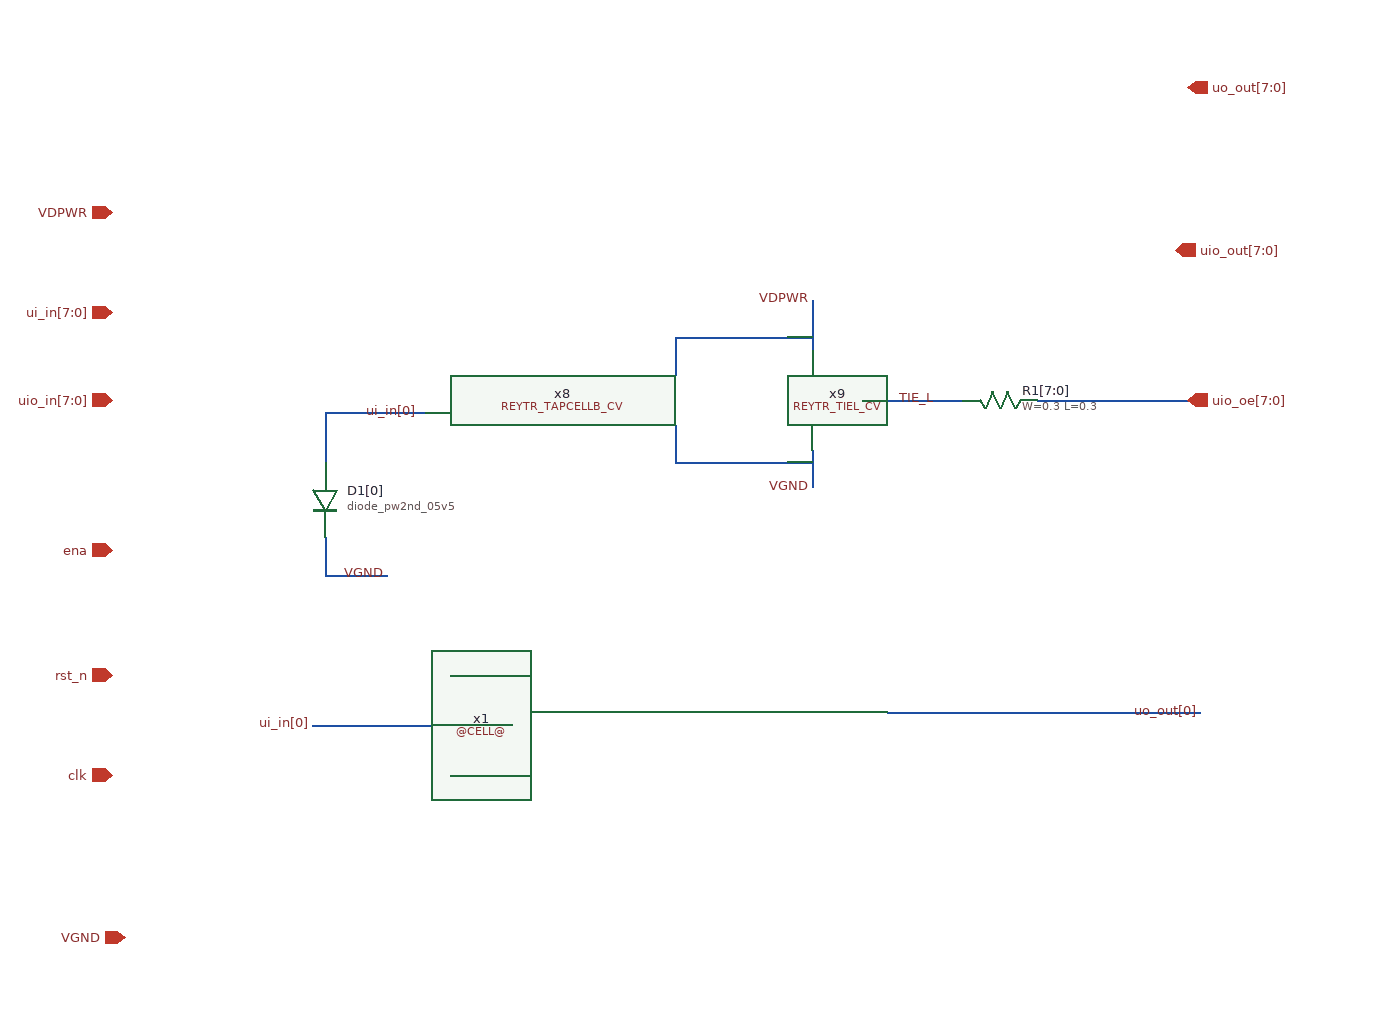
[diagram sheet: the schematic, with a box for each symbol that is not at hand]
v {xschem version=3.4.7 file_version=1.2}
G {}
K {}
V {}
S {}
E {}
N 70 -550 70 -510 {lab=VDPWR}
N 70 -430 70 -400 {lab=VGND}
N -40 -520 -40 -490 {lab=VDPWR}
N -40 -520 70 -520 {lab=VDPWR}
N -40 -450 -40 -420 {lab=VGND}
N -40 -420 70 -420 {lab=VGND}
N 110 -470 190 -470 {lab=TIE_L}
N 250 -470 300 -470 {lab=uio_oe[7:0]}
N 300 -470 370 -470 {lab=uio_oe[7:0]}
N 310 -220 380 -220 {lab=uo_out[0]}
N 130 -220 180 -220 {lab=uo_out[0]}
N -240 -210 -170 -210 {lab=ui_in[0]}
N -220 -250 -170 -250 {lab=VDPWR}
N -220 -170 -170 -170 {lab=VGND}
N 180 -220 190 -220 {lab=uo_out[0]}
N 250 -220 310 -220 {lab=uo_out[0]}
N -330 -210 -300 -210 {lab=ui_in[0]}
N 190 -220 250 -220 {lab=uo_out[0]}
N -300 -210 -240 -210 {lab=ui_in[0]}
N -320 -360 -320 -330 {lab=VGND}
N -320 -330 -270 -330 {lab=VGND}
N -320 -460 -320 -420 {lab=ui_in[0]}
N -320 -460 -240 -460 {lab=ui_in[0]}
C {devices/opin.sym} 370 -720 0 0 {name=p4 lab=uo_out[7:0]}
C {devices/opin.sym} 360 -590 0 0 {name=p6 lab=uio_out[7:0]}
C {REY_TR_SKY130A/REYTR_TAPCELLB_CV.sym} -40 -470 0 0 {name=x8 }
C {REY_TR_SKY130A/REYTR_TIEL_CV.sym} 70 -430 0 0 {name=x9 }
C {devices/lab_wire.sym} 70 -550 0 0 {name=p30 sig_type=std_logic lab=VDPWR}
C {devices/lab_wire.sym} 70 -400 0 0 {name=p31 sig_type=std_logic lab=VGND}
C {sky130_fd_pr/res_generic_m4.sym} 220 -470 1 0 {name=R1[7:0]
W=0.3
L=0.3
model=res_generic_m4
mult=1}
C {devices/opin.sym} 370 -470 0 0 {name=p32 lab=uio_oe[7:0]}
C {devices/lab_wire.sym} 170 -470 0 0 {name=p7 sig_type=std_logic lab=TIE_L}
C {devices/ipin.sym} -490 -620 0 0 {name=p1 lab=VDPWR}
C {devices/ipin.sym} -480 -40 0 0 {name=p2 lab=VGND}
C {devices/ipin.sym} -490 -540 0 0 {name=p3 lab=ui_in[7:0]}
C {devices/ipin.sym} -490 -470 0 0 {name=p5 lab=uio_in[7:0]}
C {devices/ipin.sym} -490 -350 0 0 {name=p8 lab=ena}
C {devices/ipin.sym} -490 -250 0 0 {name=p10 lab=rst_n}
C {devices/lab_wire.sym} 380 -220 0 0 {name=p12 sig_type=std_logic lab=uo_out[0]}
C {devices/lab_wire.sym} -330 -210 0 0 {name=p25 sig_type=std_logic lab=ui_in[0]}
C {devices/lab_wire.sym} -170 -170 0 0 {name=p9 sig_type=std_logic lab=VGND}
C {devices/lab_wire.sym} -170 -250 0 0 {name=p11 sig_type=std_logic lab=VDPWR}
C {@IP@/@CELL@.sym} -20 -190 0 0 {name=x1}
C {devices/ipin.sym} -490 -170 0 0 {name=p13 lab=clk
}
C {sky130_fd_pr/diode.sym} -320 -390 0 0 {name=D1[0]
model=diode_pw2nd_05v5
area=2.025e11
pj=1.8e6
spiceprefix=X
}
C {devices/lab_wire.sym} -270 -330 0 0 {name=p28 sig_type=std_logic lab=VGND}
C {devices/lab_wire.sym} -290 -460 0 1 {name=p29 sig_type=std_logic lab=ui_in[0]}
